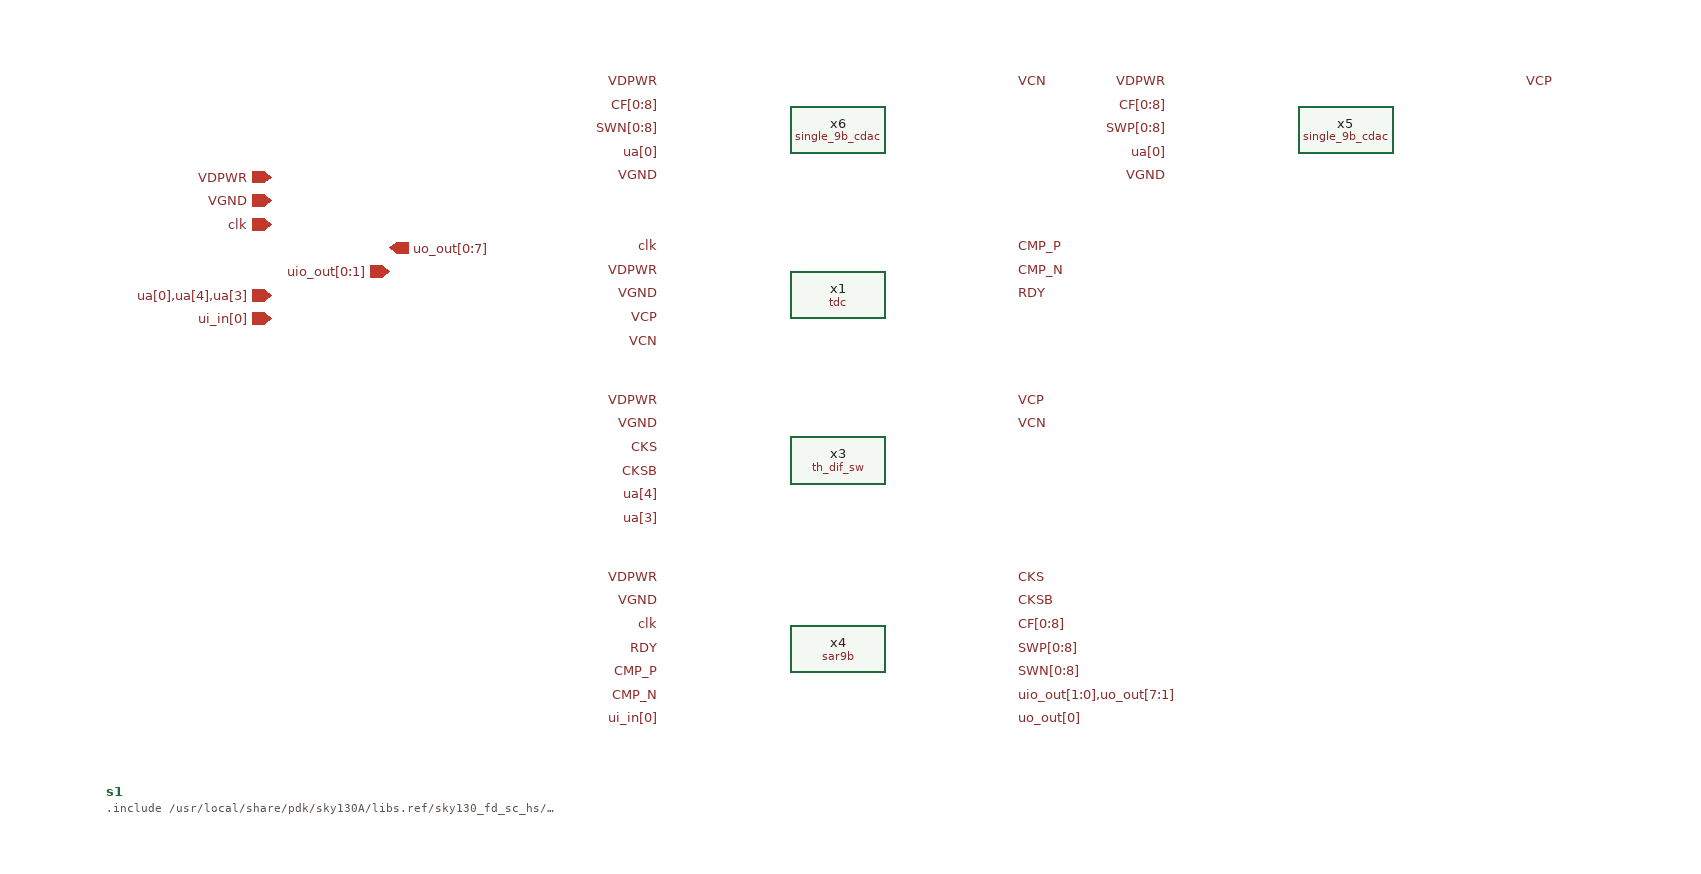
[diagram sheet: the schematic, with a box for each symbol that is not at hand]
v {xschem version=3.4.8RC file_version=1.2}
G {}
K {}
V {}
S {}
F {}
E {}
C {th_dif_sw.sym} 660 -320 0 0 {name=x3}
C {devices/lab_wire.sym} 810 -160 0 1 {name=p20 sig_type=std_logic lab=SWP[0:8]}
C {devices/lab_wire.sym} 810 -140 0 1 {name=p22 sig_type=std_logic lab=SWN[0:8]}
C {devices/lab_wire.sym} 810 -120 0 1 {name=p23 sig_type=std_logic lab="uio_out[1:0],uo_out[7:1]"}
C {devices/lab_wire.sym} 810 -100 0 1 {name=p24 sig_type=std_logic lab=uo_out[0]}
C {devices/lab_wire.sym} 810 -200 0 1 {name=p12 sig_type=std_logic lab=CKSB}
C {devices/lab_wire.sym} 810 -220 0 1 {name=p13 sig_type=std_logic lab=CKS}
C {devices/lab_wire.sym} 510 -310 0 0 {name=p1 sig_type=std_logic lab=CKSB}
C {devices/lab_wire.sym} 510 -330 0 0 {name=p2 sig_type=std_logic lab=CKS}
C {devices/lab_wire.sym} 510 -160 0 0 {name=p9 sig_type=std_logic lab=RDY}
C {devices/lab_wire.sym} 510 -140 0 0 {name=p28 sig_type=std_logic lab=CMP_P}
C {devices/lab_wire.sym} 510 -120 0 0 {name=p29 sig_type=std_logic lab=CMP_N}
C {devices/lab_wire.sym} 810 -500 0 1 {name=p4 sig_type=std_logic lab=CMP_P}
C {devices/lab_wire.sym} 810 -480 0 1 {name=p5 sig_type=std_logic lab=CMP_N}
C {devices/lab_wire.sym} 510 -290 0 0 {name=p6 sig_type=std_logic lab=ua[4]}
C {devices/lab_wire.sym} 510 -270 0 0 {name=p8 sig_type=std_logic lab=ua[3]}
C {devices/lab_wire.sym} 810 -370 0 1 {name=p10 sig_type=std_logic lab=VCP}
C {devices/lab_wire.sym} 810 -350 0 1 {name=p11 sig_type=std_logic lab=VCN}
C {devices/lab_wire.sym} 510 -440 0 0 {name=p14 sig_type=std_logic lab=VCP}
C {devices/lab_wire.sym} 510 -420 0 0 {name=p15 sig_type=std_logic lab=VCN}
C {devices/lab_wire.sym} 1240 -640 0 1 {name=p16 sig_type=std_logic lab=VCP}
C {devices/lab_wire.sym} 810 -640 0 1 {name=p17 sig_type=std_logic lab=VCN}
C {devices/lab_wire.sym} 940 -600 0 0 {name=p18 sig_type=std_logic lab=SWP[0:8]}
C {devices/lab_wire.sym} 510 -600 0 0 {name=p19 sig_type=std_logic lab=SWN[0:8]}
C {devices/lab_wire.sym} 510 -500 0 0 {name=p31 sig_type=std_logic lab=clk}
C {devices/ipin.sym} 180 -560 0 0 {name=p38 sig_type=std_logic lab=VDPWR}
C {devices/ipin.sym} 180 -540 0 0 {name=p39 sig_type=std_logic lab=VGND}
C {devices/lab_wire.sym} 810 -180 0 1 {name=p45 sig_type=std_logic lab=CF[0:8]}
C {devices/lab_wire.sym} 810 -460 0 1 {name=p46 sig_type=std_logic lab=RDY}
C {devices/lab_wire.sym} 510 -180 0 0 {name=p47 sig_type=std_logic lab=clk}
C {tdc.sym} 660 -460 0 0 {name=x1}
C {sar9b.sym} 660 -160 0 0 {name=x4}
C {devices/code_shown.sym} 40 -40 0 0 {name=s1 only_toplevel=false value=".include /usr/local/share/pdk/sky130A/libs.ref/sky130_fd_sc_hs/spice/sky130_fd_sc_hs.spice"}
C {single_9b_cdac.sym} 1090 -600 0 0 {name=x5}
C {lab_wire.sym} 940 -620 0 0 {name=p53 lab=CF[0:8]}
C {single_9b_cdac.sym} 660 -600 0 0 {name=x6}
C {lab_wire.sym} 510 -640 0 0 {name=p58 lab=VDPWR}
C {lab_wire.sym} 510 -620 0 0 {name=p59 lab=CF[0:8]}
C {lab_wire.sym} 510 -580 0 0 {name=p60 lab=ua[0]}
C {lab_wire.sym} 510 -560 0 0 {name=p61 lab=VGND}
C {lab_wire.sym} 510 -480 0 0 {name=p3 lab=VDPWR}
C {lab_wire.sym} 510 -460 0 0 {name=p7 lab=VGND}
C {lab_wire.sym} 510 -370 0 0 {name=p21 lab=VDPWR}
C {lab_wire.sym} 510 -350 0 0 {name=p25 lab=VGND}
C {lab_wire.sym} 510 -220 0 0 {name=p26 lab=VDPWR}
C {lab_wire.sym} 510 -200 0 0 {name=p27 lab=VGND}
C {devices/ipin.sym} 180 -520 0 0 {name=p0 lab=clk}
C {devices/opin.sym} 280 -500 0 0 {name=p88 lab=uo_out[0:7]}
C {devices/iopin.sym} 280 -480 0 0 {name=p89 lab=uio_out[0:1]}
C {devices/ipin.sym} 180 -440 0 0 {name=p99 lab=ui_in[0]}
C {devices/ipin.sym} 180 -460 0 0 {name=p101 lab=ua[0],ua[4],ua[3]}
C {lab_wire.sym} 940 -640 0 0 {name=p35 lab=VDPWR}
C {lab_wire.sym} 940 -560 0 0 {name=p37 lab=VGND}
C {lab_wire.sym} 940 -580 0 0 {name=p40 lab=ua[0]}
C {devices/lab_wire.sym} 510 -100 0 0 {name=p36 lab=ui_in[0]}
